# Generated by FakeRAM 2.0
VERSION 5.7 ;
BUSBITCHARS "[]" ;
PROPERTYDEFINITIONS
  MACRO width INTEGER ;
  MACRO depth INTEGER ;
  MACRO banks INTEGER ;
END PROPERTYDEFINITIONS
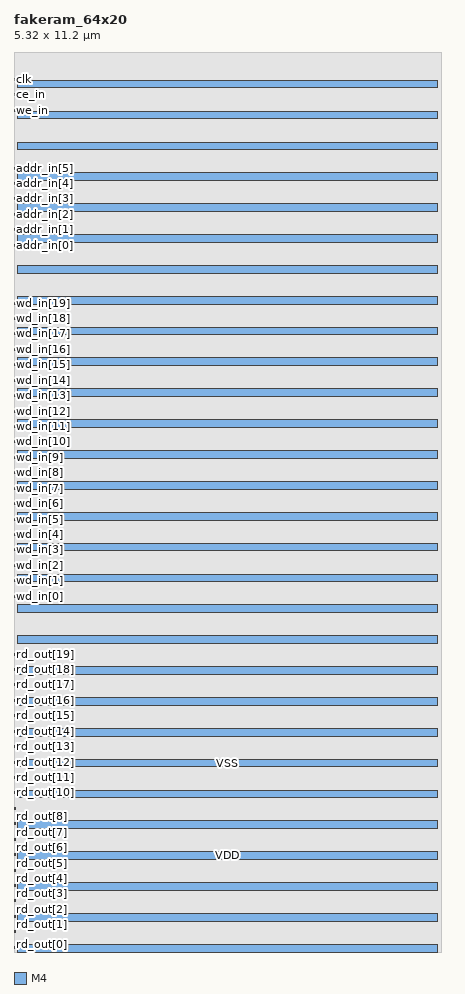
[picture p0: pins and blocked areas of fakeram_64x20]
MACRO fakeram_64x20
  PROPERTY width 20 ;
  PROPERTY depth 64 ;
  PROPERTY banks 2 ;
  FOREIGN fakeram_64x20 0 0 ;
  SYMMETRY X Y R90 ;
  SIZE 5.320 BY 11.200 ;
  CLASS BLOCK ;
  PIN rd_out[0]
    DIRECTION OUTPUT ;
    USE SIGNAL ;
    SHAPE ABUTMENT ;
    PORT
      LAYER M4 ;
      RECT 0.000 0.048 0.024 0.072 ;
    END
  END rd_out[0]
  PIN rd_out[1]
    DIRECTION OUTPUT ;
    USE SIGNAL ;
    SHAPE ABUTMENT ;
    PORT
      LAYER M4 ;
      RECT 0.000 0.240 0.024 0.264 ;
    END
  END rd_out[1]
  PIN rd_out[2]
    DIRECTION OUTPUT ;
    USE SIGNAL ;
    SHAPE ABUTMENT ;
    PORT
      LAYER M4 ;
      RECT 0.000 0.432 0.024 0.456 ;
    END
  END rd_out[2]
  PIN rd_out[3]
    DIRECTION OUTPUT ;
    USE SIGNAL ;
    SHAPE ABUTMENT ;
    PORT
      LAYER M4 ;
      RECT 0.000 0.624 0.024 0.648 ;
    END
  END rd_out[3]
  PIN rd_out[4]
    DIRECTION OUTPUT ;
    USE SIGNAL ;
    SHAPE ABUTMENT ;
    PORT
      LAYER M4 ;
      RECT 0.000 0.816 0.024 0.840 ;
    END
  END rd_out[4]
  PIN rd_out[5]
    DIRECTION OUTPUT ;
    USE SIGNAL ;
    SHAPE ABUTMENT ;
    PORT
      LAYER M4 ;
      RECT 0.000 1.008 0.024 1.032 ;
    END
  END rd_out[5]
  PIN rd_out[6]
    DIRECTION OUTPUT ;
    USE SIGNAL ;
    SHAPE ABUTMENT ;
    PORT
      LAYER M4 ;
      RECT 0.000 1.200 0.024 1.224 ;
    END
  END rd_out[6]
  PIN rd_out[7]
    DIRECTION OUTPUT ;
    USE SIGNAL ;
    SHAPE ABUTMENT ;
    PORT
      LAYER M4 ;
      RECT 0.000 1.392 0.024 1.416 ;
    END
  END rd_out[7]
  PIN rd_out[8]
    DIRECTION OUTPUT ;
    USE SIGNAL ;
    SHAPE ABUTMENT ;
    PORT
      LAYER M4 ;
      RECT 0.000 1.584 0.024 1.608 ;
    END
  END rd_out[8]
  PIN rd_out[9]
    DIRECTION OUTPUT ;
    USE SIGNAL ;
    SHAPE ABUTMENT ;
    PORT
      LAYER M4 ;
      RECT 0.000 1.776 0.024 1.800 ;
    END
  END rd_out[9]
  PIN rd_out[10]
    DIRECTION OUTPUT ;
    USE SIGNAL ;
    SHAPE ABUTMENT ;
    PORT
      LAYER M4 ;
      RECT 0.000 1.968 0.024 1.992 ;
    END
  END rd_out[10]
  PIN rd_out[11]
    DIRECTION OUTPUT ;
    USE SIGNAL ;
    SHAPE ABUTMENT ;
    PORT
      LAYER M4 ;
      RECT 0.000 2.160 0.024 2.184 ;
    END
  END rd_out[11]
  PIN rd_out[12]
    DIRECTION OUTPUT ;
    USE SIGNAL ;
    SHAPE ABUTMENT ;
    PORT
      LAYER M4 ;
      RECT 0.000 2.352 0.024 2.376 ;
    END
  END rd_out[12]
  PIN rd_out[13]
    DIRECTION OUTPUT ;
    USE SIGNAL ;
    SHAPE ABUTMENT ;
    PORT
      LAYER M4 ;
      RECT 0.000 2.544 0.024 2.568 ;
    END
  END rd_out[13]
  PIN rd_out[14]
    DIRECTION OUTPUT ;
    USE SIGNAL ;
    SHAPE ABUTMENT ;
    PORT
      LAYER M4 ;
      RECT 0.000 2.736 0.024 2.760 ;
    END
  END rd_out[14]
  PIN rd_out[15]
    DIRECTION OUTPUT ;
    USE SIGNAL ;
    SHAPE ABUTMENT ;
    PORT
      LAYER M4 ;
      RECT 0.000 2.928 0.024 2.952 ;
    END
  END rd_out[15]
  PIN rd_out[16]
    DIRECTION OUTPUT ;
    USE SIGNAL ;
    SHAPE ABUTMENT ;
    PORT
      LAYER M4 ;
      RECT 0.000 3.120 0.024 3.144 ;
    END
  END rd_out[16]
  PIN rd_out[17]
    DIRECTION OUTPUT ;
    USE SIGNAL ;
    SHAPE ABUTMENT ;
    PORT
      LAYER M4 ;
      RECT 0.000 3.312 0.024 3.336 ;
    END
  END rd_out[17]
  PIN rd_out[18]
    DIRECTION OUTPUT ;
    USE SIGNAL ;
    SHAPE ABUTMENT ;
    PORT
      LAYER M4 ;
      RECT 0.000 3.504 0.024 3.528 ;
    END
  END rd_out[18]
  PIN rd_out[19]
    DIRECTION OUTPUT ;
    USE SIGNAL ;
    SHAPE ABUTMENT ;
    PORT
      LAYER M4 ;
      RECT 0.000 3.696 0.024 3.720 ;
    END
  END rd_out[19]
  PIN wd_in[0]
    DIRECTION INPUT ;
    USE SIGNAL ;
    SHAPE ABUTMENT ;
    PORT
      LAYER M4 ;
      RECT 0.000 4.416 0.024 4.440 ;
    END
  END wd_in[0]
  PIN wd_in[1]
    DIRECTION INPUT ;
    USE SIGNAL ;
    SHAPE ABUTMENT ;
    PORT
      LAYER M4 ;
      RECT 0.000 4.608 0.024 4.632 ;
    END
  END wd_in[1]
  PIN wd_in[2]
    DIRECTION INPUT ;
    USE SIGNAL ;
    SHAPE ABUTMENT ;
    PORT
      LAYER M4 ;
      RECT 0.000 4.800 0.024 4.824 ;
    END
  END wd_in[2]
  PIN wd_in[3]
    DIRECTION INPUT ;
    USE SIGNAL ;
    SHAPE ABUTMENT ;
    PORT
      LAYER M4 ;
      RECT 0.000 4.992 0.024 5.016 ;
    END
  END wd_in[3]
  PIN wd_in[4]
    DIRECTION INPUT ;
    USE SIGNAL ;
    SHAPE ABUTMENT ;
    PORT
      LAYER M4 ;
      RECT 0.000 5.184 0.024 5.208 ;
    END
  END wd_in[4]
  PIN wd_in[5]
    DIRECTION INPUT ;
    USE SIGNAL ;
    SHAPE ABUTMENT ;
    PORT
      LAYER M4 ;
      RECT 0.000 5.376 0.024 5.400 ;
    END
  END wd_in[5]
  PIN wd_in[6]
    DIRECTION INPUT ;
    USE SIGNAL ;
    SHAPE ABUTMENT ;
    PORT
      LAYER M4 ;
      RECT 0.000 5.568 0.024 5.592 ;
    END
  END wd_in[6]
  PIN wd_in[7]
    DIRECTION INPUT ;
    USE SIGNAL ;
    SHAPE ABUTMENT ;
    PORT
      LAYER M4 ;
      RECT 0.000 5.760 0.024 5.784 ;
    END
  END wd_in[7]
  PIN wd_in[8]
    DIRECTION INPUT ;
    USE SIGNAL ;
    SHAPE ABUTMENT ;
    PORT
      LAYER M4 ;
      RECT 0.000 5.952 0.024 5.976 ;
    END
  END wd_in[8]
  PIN wd_in[9]
    DIRECTION INPUT ;
    USE SIGNAL ;
    SHAPE ABUTMENT ;
    PORT
      LAYER M4 ;
      RECT 0.000 6.144 0.024 6.168 ;
    END
  END wd_in[9]
  PIN wd_in[10]
    DIRECTION INPUT ;
    USE SIGNAL ;
    SHAPE ABUTMENT ;
    PORT
      LAYER M4 ;
      RECT 0.000 6.336 0.024 6.360 ;
    END
  END wd_in[10]
  PIN wd_in[11]
    DIRECTION INPUT ;
    USE SIGNAL ;
    SHAPE ABUTMENT ;
    PORT
      LAYER M4 ;
      RECT 0.000 6.528 0.024 6.552 ;
    END
  END wd_in[11]
  PIN wd_in[12]
    DIRECTION INPUT ;
    USE SIGNAL ;
    SHAPE ABUTMENT ;
    PORT
      LAYER M4 ;
      RECT 0.000 6.720 0.024 6.744 ;
    END
  END wd_in[12]
  PIN wd_in[13]
    DIRECTION INPUT ;
    USE SIGNAL ;
    SHAPE ABUTMENT ;
    PORT
      LAYER M4 ;
      RECT 0.000 6.912 0.024 6.936 ;
    END
  END wd_in[13]
  PIN wd_in[14]
    DIRECTION INPUT ;
    USE SIGNAL ;
    SHAPE ABUTMENT ;
    PORT
      LAYER M4 ;
      RECT 0.000 7.104 0.024 7.128 ;
    END
  END wd_in[14]
  PIN wd_in[15]
    DIRECTION INPUT ;
    USE SIGNAL ;
    SHAPE ABUTMENT ;
    PORT
      LAYER M4 ;
      RECT 0.000 7.296 0.024 7.320 ;
    END
  END wd_in[15]
  PIN wd_in[16]
    DIRECTION INPUT ;
    USE SIGNAL ;
    SHAPE ABUTMENT ;
    PORT
      LAYER M4 ;
      RECT 0.000 7.488 0.024 7.512 ;
    END
  END wd_in[16]
  PIN wd_in[17]
    DIRECTION INPUT ;
    USE SIGNAL ;
    SHAPE ABUTMENT ;
    PORT
      LAYER M4 ;
      RECT 0.000 7.680 0.024 7.704 ;
    END
  END wd_in[17]
  PIN wd_in[18]
    DIRECTION INPUT ;
    USE SIGNAL ;
    SHAPE ABUTMENT ;
    PORT
      LAYER M4 ;
      RECT 0.000 7.872 0.024 7.896 ;
    END
  END wd_in[18]
  PIN wd_in[19]
    DIRECTION INPUT ;
    USE SIGNAL ;
    SHAPE ABUTMENT ;
    PORT
      LAYER M4 ;
      RECT 0.000 8.064 0.024 8.088 ;
    END
  END wd_in[19]
  PIN addr_in[0]
    DIRECTION INPUT ;
    USE SIGNAL ;
    SHAPE ABUTMENT ;
    PORT
      LAYER M4 ;
      RECT 0.000 8.784 0.024 8.808 ;
    END
  END addr_in[0]
  PIN addr_in[1]
    DIRECTION INPUT ;
    USE SIGNAL ;
    SHAPE ABUTMENT ;
    PORT
      LAYER M4 ;
      RECT 0.000 8.976 0.024 9.000 ;
    END
  END addr_in[1]
  PIN addr_in[2]
    DIRECTION INPUT ;
    USE SIGNAL ;
    SHAPE ABUTMENT ;
    PORT
      LAYER M4 ;
      RECT 0.000 9.168 0.024 9.192 ;
    END
  END addr_in[2]
  PIN addr_in[3]
    DIRECTION INPUT ;
    USE SIGNAL ;
    SHAPE ABUTMENT ;
    PORT
      LAYER M4 ;
      RECT 0.000 9.360 0.024 9.384 ;
    END
  END addr_in[3]
  PIN addr_in[4]
    DIRECTION INPUT ;
    USE SIGNAL ;
    SHAPE ABUTMENT ;
    PORT
      LAYER M4 ;
      RECT 0.000 9.552 0.024 9.576 ;
    END
  END addr_in[4]
  PIN addr_in[5]
    DIRECTION INPUT ;
    USE SIGNAL ;
    SHAPE ABUTMENT ;
    PORT
      LAYER M4 ;
      RECT 0.000 9.744 0.024 9.768 ;
    END
  END addr_in[5]
  PIN we_in
    DIRECTION INPUT ;
    USE SIGNAL ;
    SHAPE ABUTMENT ;
    PORT
      LAYER M4 ;
      RECT 0.000 10.464 0.024 10.488 ;
    END
  END we_in
  PIN ce_in
    DIRECTION INPUT ;
    USE SIGNAL ;
    SHAPE ABUTMENT ;
    PORT
      LAYER M4 ;
      RECT 0.000 10.656 0.024 10.680 ;
    END
  END ce_in
  PIN clk
    DIRECTION INPUT ;
    USE SIGNAL ;
    SHAPE ABUTMENT ;
    PORT
      LAYER M4 ;
      RECT 0.000 10.848 0.024 10.872 ;
    END
  END clk
  PIN VSS
    DIRECTION INOUT ;
    USE GROUND ;
    PORT
      LAYER M4 ;
      RECT 0.048 0.000 5.272 0.096 ;
      RECT 0.048 0.768 5.272 0.864 ;
      RECT 0.048 1.536 5.272 1.632 ;
      RECT 0.048 2.304 5.272 2.400 ;
      RECT 0.048 3.072 5.272 3.168 ;
      RECT 0.048 3.840 5.272 3.936 ;
      RECT 0.048 4.608 5.272 4.704 ;
      RECT 0.048 5.376 5.272 5.472 ;
      RECT 0.048 6.144 5.272 6.240 ;
      RECT 0.048 6.912 5.272 7.008 ;
      RECT 0.048 7.680 5.272 7.776 ;
      RECT 0.048 8.448 5.272 8.544 ;
      RECT 0.048 9.216 5.272 9.312 ;
      RECT 0.048 9.984 5.272 10.080 ;
      RECT 0.048 10.752 5.272 10.848 ;
    END
  END VSS
  PIN VDD
    DIRECTION INOUT ;
    USE POWER ;
    PORT
      LAYER M4 ;
      RECT 0.048 0.384 5.272 0.480 ;
      RECT 0.048 1.152 5.272 1.248 ;
      RECT 0.048 1.920 5.272 2.016 ;
      RECT 0.048 2.688 5.272 2.784 ;
      RECT 0.048 3.456 5.272 3.552 ;
      RECT 0.048 4.224 5.272 4.320 ;
      RECT 0.048 4.992 5.272 5.088 ;
      RECT 0.048 5.760 5.272 5.856 ;
      RECT 0.048 6.528 5.272 6.624 ;
      RECT 0.048 7.296 5.272 7.392 ;
      RECT 0.048 8.064 5.272 8.160 ;
      RECT 0.048 8.832 5.272 8.928 ;
      RECT 0.048 9.600 5.272 9.696 ;
      RECT 0.048 10.368 5.272 10.464 ;
    END
  END VDD
  OBS
    LAYER M1 ;
    RECT 0 0 5.320 11.200 ;
    LAYER M2 ;
    RECT 0 0 5.320 11.200 ;
    LAYER M3 ;
    RECT 0 0 5.320 11.200 ;
    LAYER M4 ;
    RECT 0 0 5.320 11.200 ;
  END
END fakeram_64x20

END LIBRARY
